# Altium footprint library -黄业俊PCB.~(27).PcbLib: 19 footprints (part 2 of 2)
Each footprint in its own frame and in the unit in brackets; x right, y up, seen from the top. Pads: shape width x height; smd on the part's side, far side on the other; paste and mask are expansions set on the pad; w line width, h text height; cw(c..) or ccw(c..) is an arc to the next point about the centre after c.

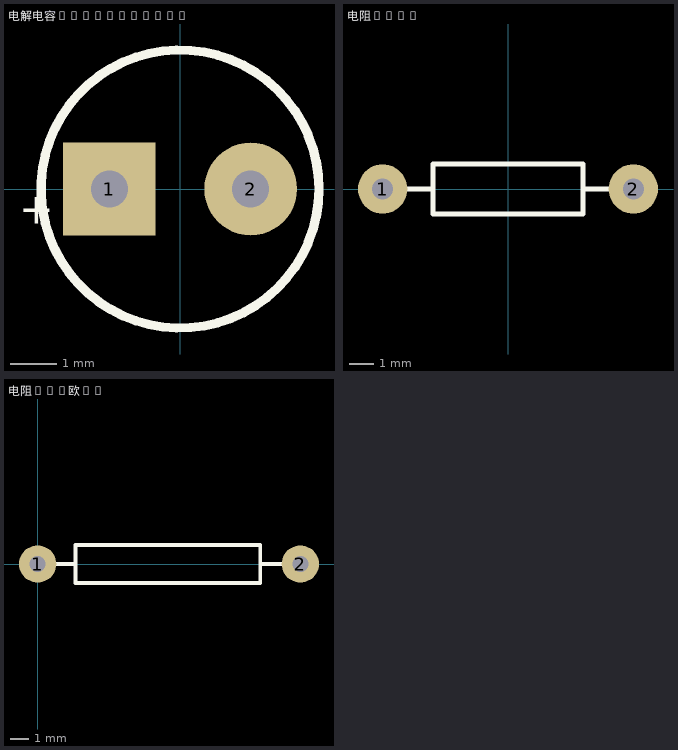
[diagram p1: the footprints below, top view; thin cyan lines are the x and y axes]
## 电解电容100uf/220uf [mm]
pads (2):
  rect 2x2 hole 0.8: 1(-1.524,0)
  round 2 hole 0.8: 2(1.524,0)
Top Overlay:
  circle w0.2: c0,0 r3
  text "+" at -3.475,-0.75 h0.65

## 电阻1/4W [mm]
pads (2):
  round 2 hole 0.85: 1(-5.08,0) 2(5.08,0)
Top Overlay:
  lines w0.2: -4.064,0 -3.048,0 ; 3.048,0 4.064,0 ; -3.048,-1.016 -3.048,1.016 3.048,1.016 3.048,-1.016 -3.048,-1.016

## 电阻2.2欧1W [mm]
pads (2):
  round 2 hole 0.85: 1(0,0) 2(14.097,0)
Top Overlay:
  lines w0.2: 1.016,0 2.032,0 ; 12.065,0 13.081,0 ; 2.032,-1.016 2.032,1.016 11.938,1.016 11.938,-1.016 2.032,-1.016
